VERSION 5.8 ;
BUSBITCHARS "[]" ;
DIVIDERCHAR "/" ;
UNITS
    DATABASE MICRONS 1000 ;
END UNITS

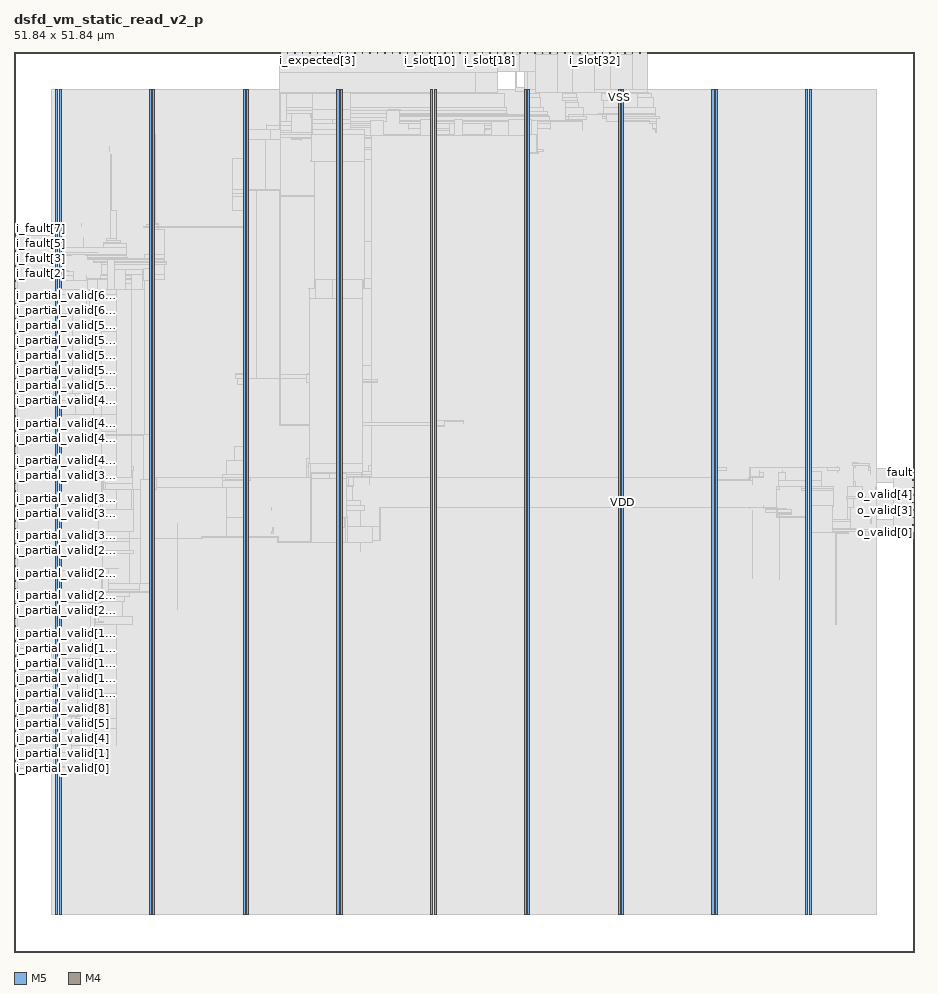
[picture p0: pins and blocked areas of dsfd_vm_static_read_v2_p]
MACRO dsfd_vm_static_read_v2_p
  FOREIGN dsfd_vm_static_read_v2_p 0 0 ;
  CLASS BLOCK ;
  SIZE 51.84 BY 51.84 ;
  PIN ck
    DIRECTION INPUT ;
    USE SIGNAL ;
    PORT
      LAYER M5 ;
        RECT  15.312 51.756 15.336 51.84 ;
    END
  END ck
  PIN fault
    DIRECTION OUTPUT ;
    USE SIGNAL ;
    PORT
      LAYER M4 ;
        RECT  51.756 27.6 51.84 27.624 ;
    END
  END fault
  PIN i_expected[0]
    DIRECTION INPUT ;
    USE SIGNAL ;
    PORT
      LAYER M5 ;
        RECT  16.176 51.756 16.2 51.84 ;
    END
  END i_expected[0]
  PIN i_expected[1]
    DIRECTION INPUT ;
    USE SIGNAL ;
    PORT
      LAYER M5 ;
        RECT  16.608 51.756 16.632 51.84 ;
    END
  END i_expected[1]
  PIN i_expected[2]
    DIRECTION INPUT ;
    USE SIGNAL ;
    PORT
      LAYER M5 ;
        RECT  17.04 51.756 17.064 51.84 ;
    END
  END i_expected[2]
  PIN i_expected[3]
    DIRECTION INPUT ;
    USE SIGNAL ;
    PORT
      LAYER M5 ;
        RECT  17.472 51.756 17.496 51.84 ;
    END
  END i_expected[3]
  PIN i_expected[4]
    DIRECTION INPUT ;
    USE SIGNAL ;
    PORT
      LAYER M5 ;
        RECT  17.904 51.756 17.928 51.84 ;
    END
  END i_expected[4]
  PIN i_expected[5]
    DIRECTION INPUT ;
    USE SIGNAL ;
    PORT
      LAYER M5 ;
        RECT  18.336 51.756 18.36 51.84 ;
    END
  END i_expected[5]
  PIN i_expected[6]
    DIRECTION INPUT ;
    USE SIGNAL ;
    PORT
      LAYER M5 ;
        RECT  18.768 51.756 18.792 51.84 ;
    END
  END i_expected[6]
  PIN i_expected[7]
    DIRECTION INPUT ;
    USE SIGNAL ;
    PORT
      LAYER M5 ;
        RECT  19.2 51.756 19.224 51.84 ;
    END
  END i_expected[7]
  PIN i_fault[0]
    DIRECTION INPUT ;
    USE SIGNAL ;
    PORT
      LAYER M4 ;
        RECT  0 38.208 0.084 38.232 ;
    END
  END i_fault[0]
  PIN i_fault[1]
    DIRECTION INPUT ;
    USE SIGNAL ;
    PORT
      LAYER M4 ;
        RECT  0 38.64 0.084 38.664 ;
    END
  END i_fault[1]
  PIN i_fault[2]
    DIRECTION INPUT ;
    USE SIGNAL ;
    PORT
      LAYER M4 ;
        RECT  0 39.072 0.084 39.096 ;
    END
  END i_fault[2]
  PIN i_fault[3]
    DIRECTION INPUT ;
    USE SIGNAL ;
    PORT
      LAYER M4 ;
        RECT  0 39.504 0.084 39.528 ;
    END
  END i_fault[3]
  PIN i_fault[4]
    DIRECTION INPUT ;
    USE SIGNAL ;
    PORT
      LAYER M4 ;
        RECT  0 39.936 0.084 39.96 ;
    END
  END i_fault[4]
  PIN i_fault[5]
    DIRECTION INPUT ;
    USE SIGNAL ;
    PORT
      LAYER M4 ;
        RECT  0 40.368 0.084 40.392 ;
    END
  END i_fault[5]
  PIN i_fault[6]
    DIRECTION INPUT ;
    USE SIGNAL ;
    PORT
      LAYER M4 ;
        RECT  0 40.8 0.084 40.824 ;
    END
  END i_fault[6]
  PIN i_fault[7]
    DIRECTION INPUT ;
    USE SIGNAL ;
    PORT
      LAYER M4 ;
        RECT  0 41.232 0.084 41.256 ;
    END
  END i_fault[7]
  PIN i_partial_valid[0]
    DIRECTION INPUT ;
    USE SIGNAL ;
    PORT
      LAYER M4 ;
        RECT  0 10.56 0.084 10.584 ;
    END
  END i_partial_valid[0]
  PIN i_partial_valid[10]
    DIRECTION INPUT ;
    USE SIGNAL ;
    PORT
      LAYER M4 ;
        RECT  0 14.88 0.084 14.904 ;
    END
  END i_partial_valid[10]
  PIN i_partial_valid[11]
    DIRECTION INPUT ;
    USE SIGNAL ;
    PORT
      LAYER M4 ;
        RECT  0 15.312 0.084 15.336 ;
    END
  END i_partial_valid[11]
  PIN i_partial_valid[12]
    DIRECTION INPUT ;
    USE SIGNAL ;
    PORT
      LAYER M4 ;
        RECT  0 15.744 0.084 15.768 ;
    END
  END i_partial_valid[12]
  PIN i_partial_valid[13]
    DIRECTION INPUT ;
    USE SIGNAL ;
    PORT
      LAYER M4 ;
        RECT  0 16.176 0.084 16.2 ;
    END
  END i_partial_valid[13]
  PIN i_partial_valid[14]
    DIRECTION INPUT ;
    USE SIGNAL ;
    PORT
      LAYER M4 ;
        RECT  0 16.608 0.084 16.632 ;
    END
  END i_partial_valid[14]
  PIN i_partial_valid[15]
    DIRECTION INPUT ;
    USE SIGNAL ;
    PORT
      LAYER M4 ;
        RECT  0 17.04 0.084 17.064 ;
    END
  END i_partial_valid[15]
  PIN i_partial_valid[16]
    DIRECTION INPUT ;
    USE SIGNAL ;
    PORT
      LAYER M4 ;
        RECT  0 17.472 0.084 17.496 ;
    END
  END i_partial_valid[16]
  PIN i_partial_valid[17]
    DIRECTION INPUT ;
    USE SIGNAL ;
    PORT
      LAYER M4 ;
        RECT  0 17.904 0.084 17.928 ;
    END
  END i_partial_valid[17]
  PIN i_partial_valid[18]
    DIRECTION INPUT ;
    USE SIGNAL ;
    PORT
      LAYER M4 ;
        RECT  0 18.336 0.084 18.36 ;
    END
  END i_partial_valid[18]
  PIN i_partial_valid[19]
    DIRECTION INPUT ;
    USE SIGNAL ;
    PORT
      LAYER M4 ;
        RECT  0 18.768 0.084 18.792 ;
    END
  END i_partial_valid[19]
  PIN i_partial_valid[1]
    DIRECTION INPUT ;
    USE SIGNAL ;
    PORT
      LAYER M4 ;
        RECT  0 10.992 0.084 11.016 ;
    END
  END i_partial_valid[1]
  PIN i_partial_valid[20]
    DIRECTION INPUT ;
    USE SIGNAL ;
    PORT
      LAYER M4 ;
        RECT  0 19.2 0.084 19.224 ;
    END
  END i_partial_valid[20]
  PIN i_partial_valid[21]
    DIRECTION INPUT ;
    USE SIGNAL ;
    PORT
      LAYER M4 ;
        RECT  0 19.632 0.084 19.656 ;
    END
  END i_partial_valid[21]
  PIN i_partial_valid[22]
    DIRECTION INPUT ;
    USE SIGNAL ;
    PORT
      LAYER M4 ;
        RECT  0 20.064 0.084 20.088 ;
    END
  END i_partial_valid[22]
  PIN i_partial_valid[23]
    DIRECTION INPUT ;
    USE SIGNAL ;
    PORT
      LAYER M4 ;
        RECT  0 20.496 0.084 20.52 ;
    END
  END i_partial_valid[23]
  PIN i_partial_valid[24]
    DIRECTION INPUT ;
    USE SIGNAL ;
    PORT
      LAYER M4 ;
        RECT  0 20.928 0.084 20.952 ;
    END
  END i_partial_valid[24]
  PIN i_partial_valid[25]
    DIRECTION INPUT ;
    USE SIGNAL ;
    PORT
      LAYER M4 ;
        RECT  0 21.36 0.084 21.384 ;
    END
  END i_partial_valid[25]
  PIN i_partial_valid[26]
    DIRECTION INPUT ;
    USE SIGNAL ;
    PORT
      LAYER M4 ;
        RECT  0 21.792 0.084 21.816 ;
    END
  END i_partial_valid[26]
  PIN i_partial_valid[27]
    DIRECTION INPUT ;
    USE SIGNAL ;
    PORT
      LAYER M4 ;
        RECT  0 22.224 0.084 22.248 ;
    END
  END i_partial_valid[27]
  PIN i_partial_valid[28]
    DIRECTION INPUT ;
    USE SIGNAL ;
    PORT
      LAYER M4 ;
        RECT  0 22.656 0.084 22.68 ;
    END
  END i_partial_valid[28]
  PIN i_partial_valid[29]
    DIRECTION INPUT ;
    USE SIGNAL ;
    PORT
      LAYER M4 ;
        RECT  0 23.088 0.084 23.112 ;
    END
  END i_partial_valid[29]
  PIN i_partial_valid[2]
    DIRECTION INPUT ;
    USE SIGNAL ;
    PORT
      LAYER M4 ;
        RECT  0 11.424 0.084 11.448 ;
    END
  END i_partial_valid[2]
  PIN i_partial_valid[30]
    DIRECTION INPUT ;
    USE SIGNAL ;
    PORT
      LAYER M4 ;
        RECT  0 23.52 0.084 23.544 ;
    END
  END i_partial_valid[30]
  PIN i_partial_valid[31]
    DIRECTION INPUT ;
    USE SIGNAL ;
    PORT
      LAYER M4 ;
        RECT  0 23.952 0.084 23.976 ;
    END
  END i_partial_valid[31]
  PIN i_partial_valid[32]
    DIRECTION INPUT ;
    USE SIGNAL ;
    PORT
      LAYER M4 ;
        RECT  0 24.384 0.084 24.408 ;
    END
  END i_partial_valid[32]
  PIN i_partial_valid[33]
    DIRECTION INPUT ;
    USE SIGNAL ;
    PORT
      LAYER M4 ;
        RECT  0 24.816 0.084 24.84 ;
    END
  END i_partial_valid[33]
  PIN i_partial_valid[34]
    DIRECTION INPUT ;
    USE SIGNAL ;
    PORT
      LAYER M4 ;
        RECT  0 25.248 0.084 25.272 ;
    END
  END i_partial_valid[34]
  PIN i_partial_valid[35]
    DIRECTION INPUT ;
    USE SIGNAL ;
    PORT
      LAYER M4 ;
        RECT  0 25.68 0.084 25.704 ;
    END
  END i_partial_valid[35]
  PIN i_partial_valid[36]
    DIRECTION INPUT ;
    USE SIGNAL ;
    PORT
      LAYER M4 ;
        RECT  0 26.112 0.084 26.136 ;
    END
  END i_partial_valid[36]
  PIN i_partial_valid[37]
    DIRECTION INPUT ;
    USE SIGNAL ;
    PORT
      LAYER M4 ;
        RECT  0 26.544 0.084 26.568 ;
    END
  END i_partial_valid[37]
  PIN i_partial_valid[38]
    DIRECTION INPUT ;
    USE SIGNAL ;
    PORT
      LAYER M4 ;
        RECT  0 26.976 0.084 27 ;
    END
  END i_partial_valid[38]
  PIN i_partial_valid[39]
    DIRECTION INPUT ;
    USE SIGNAL ;
    PORT
      LAYER M4 ;
        RECT  0 27.408 0.084 27.432 ;
    END
  END i_partial_valid[39]
  PIN i_partial_valid[3]
    DIRECTION INPUT ;
    USE SIGNAL ;
    PORT
      LAYER M4 ;
        RECT  0 11.856 0.084 11.88 ;
    END
  END i_partial_valid[3]
  PIN i_partial_valid[40]
    DIRECTION INPUT ;
    USE SIGNAL ;
    PORT
      LAYER M4 ;
        RECT  0 27.84 0.084 27.864 ;
    END
  END i_partial_valid[40]
  PIN i_partial_valid[41]
    DIRECTION INPUT ;
    USE SIGNAL ;
    PORT
      LAYER M4 ;
        RECT  0 28.272 0.084 28.296 ;
    END
  END i_partial_valid[41]
  PIN i_partial_valid[42]
    DIRECTION INPUT ;
    USE SIGNAL ;
    PORT
      LAYER M4 ;
        RECT  0 28.704 0.084 28.728 ;
    END
  END i_partial_valid[42]
  PIN i_partial_valid[43]
    DIRECTION INPUT ;
    USE SIGNAL ;
    PORT
      LAYER M4 ;
        RECT  0 29.136 0.084 29.16 ;
    END
  END i_partial_valid[43]
  PIN i_partial_valid[44]
    DIRECTION INPUT ;
    USE SIGNAL ;
    PORT
      LAYER M4 ;
        RECT  0 29.568 0.084 29.592 ;
    END
  END i_partial_valid[44]
  PIN i_partial_valid[45]
    DIRECTION INPUT ;
    USE SIGNAL ;
    PORT
      LAYER M4 ;
        RECT  0 30 0.084 30.024 ;
    END
  END i_partial_valid[45]
  PIN i_partial_valid[46]
    DIRECTION INPUT ;
    USE SIGNAL ;
    PORT
      LAYER M4 ;
        RECT  0 30.432 0.084 30.456 ;
    END
  END i_partial_valid[46]
  PIN i_partial_valid[47]
    DIRECTION INPUT ;
    USE SIGNAL ;
    PORT
      LAYER M4 ;
        RECT  0 30.864 0.084 30.888 ;
    END
  END i_partial_valid[47]
  PIN i_partial_valid[48]
    DIRECTION INPUT ;
    USE SIGNAL ;
    PORT
      LAYER M4 ;
        RECT  0 31.296 0.084 31.32 ;
    END
  END i_partial_valid[48]
  PIN i_partial_valid[49]
    DIRECTION INPUT ;
    USE SIGNAL ;
    PORT
      LAYER M4 ;
        RECT  0 31.728 0.084 31.752 ;
    END
  END i_partial_valid[49]
  PIN i_partial_valid[4]
    DIRECTION INPUT ;
    USE SIGNAL ;
    PORT
      LAYER M4 ;
        RECT  0 12.288 0.084 12.312 ;
    END
  END i_partial_valid[4]
  PIN i_partial_valid[50]
    DIRECTION INPUT ;
    USE SIGNAL ;
    PORT
      LAYER M4 ;
        RECT  0 32.16 0.084 32.184 ;
    END
  END i_partial_valid[50]
  PIN i_partial_valid[51]
    DIRECTION INPUT ;
    USE SIGNAL ;
    PORT
      LAYER M4 ;
        RECT  0 32.592 0.084 32.616 ;
    END
  END i_partial_valid[51]
  PIN i_partial_valid[52]
    DIRECTION INPUT ;
    USE SIGNAL ;
    PORT
      LAYER M4 ;
        RECT  0 33.024 0.084 33.048 ;
    END
  END i_partial_valid[52]
  PIN i_partial_valid[53]
    DIRECTION INPUT ;
    USE SIGNAL ;
    PORT
      LAYER M4 ;
        RECT  0 33.456 0.084 33.48 ;
    END
  END i_partial_valid[53]
  PIN i_partial_valid[54]
    DIRECTION INPUT ;
    USE SIGNAL ;
    PORT
      LAYER M4 ;
        RECT  0 33.888 0.084 33.912 ;
    END
  END i_partial_valid[54]
  PIN i_partial_valid[55]
    DIRECTION INPUT ;
    USE SIGNAL ;
    PORT
      LAYER M4 ;
        RECT  0 34.32 0.084 34.344 ;
    END
  END i_partial_valid[55]
  PIN i_partial_valid[56]
    DIRECTION INPUT ;
    USE SIGNAL ;
    PORT
      LAYER M4 ;
        RECT  0 34.752 0.084 34.776 ;
    END
  END i_partial_valid[56]
  PIN i_partial_valid[57]
    DIRECTION INPUT ;
    USE SIGNAL ;
    PORT
      LAYER M4 ;
        RECT  0 35.184 0.084 35.208 ;
    END
  END i_partial_valid[57]
  PIN i_partial_valid[58]
    DIRECTION INPUT ;
    USE SIGNAL ;
    PORT
      LAYER M4 ;
        RECT  0 35.616 0.084 35.64 ;
    END
  END i_partial_valid[58]
  PIN i_partial_valid[59]
    DIRECTION INPUT ;
    USE SIGNAL ;
    PORT
      LAYER M4 ;
        RECT  0 36.048 0.084 36.072 ;
    END
  END i_partial_valid[59]
  PIN i_partial_valid[5]
    DIRECTION INPUT ;
    USE SIGNAL ;
    PORT
      LAYER M4 ;
        RECT  0 12.72 0.084 12.744 ;
    END
  END i_partial_valid[5]
  PIN i_partial_valid[60]
    DIRECTION INPUT ;
    USE SIGNAL ;
    PORT
      LAYER M4 ;
        RECT  0 36.48 0.084 36.504 ;
    END
  END i_partial_valid[60]
  PIN i_partial_valid[61]
    DIRECTION INPUT ;
    USE SIGNAL ;
    PORT
      LAYER M4 ;
        RECT  0 36.912 0.084 36.936 ;
    END
  END i_partial_valid[61]
  PIN i_partial_valid[62]
    DIRECTION INPUT ;
    USE SIGNAL ;
    PORT
      LAYER M4 ;
        RECT  0 37.344 0.084 37.368 ;
    END
  END i_partial_valid[62]
  PIN i_partial_valid[63]
    DIRECTION INPUT ;
    USE SIGNAL ;
    PORT
      LAYER M4 ;
        RECT  0 37.776 0.084 37.8 ;
    END
  END i_partial_valid[63]
  PIN i_partial_valid[6]
    DIRECTION INPUT ;
    USE SIGNAL ;
    PORT
      LAYER M4 ;
        RECT  0 13.152 0.084 13.176 ;
    END
  END i_partial_valid[6]
  PIN i_partial_valid[7]
    DIRECTION INPUT ;
    USE SIGNAL ;
    PORT
      LAYER M4 ;
        RECT  0 13.584 0.084 13.608 ;
    END
  END i_partial_valid[7]
  PIN i_partial_valid[8]
    DIRECTION INPUT ;
    USE SIGNAL ;
    PORT
      LAYER M4 ;
        RECT  0 14.016 0.084 14.04 ;
    END
  END i_partial_valid[8]
  PIN i_partial_valid[9]
    DIRECTION INPUT ;
    USE SIGNAL ;
    PORT
      LAYER M4 ;
        RECT  0 14.448 0.084 14.472 ;
    END
  END i_partial_valid[9]
  PIN i_slot[0]
    DIRECTION INPUT ;
    USE SIGNAL ;
    PORT
      LAYER M5 ;
        RECT  19.632 51.756 19.656 51.84 ;
    END
  END i_slot[0]
  PIN i_slot[10]
    DIRECTION INPUT ;
    USE SIGNAL ;
    PORT
      LAYER M5 ;
        RECT  23.952 51.756 23.976 51.84 ;
    END
  END i_slot[10]
  PIN i_slot[11]
    DIRECTION INPUT ;
    USE SIGNAL ;
    PORT
      LAYER M5 ;
        RECT  24.384 51.756 24.408 51.84 ;
    END
  END i_slot[11]
  PIN i_slot[12]
    DIRECTION INPUT ;
    USE SIGNAL ;
    PORT
      LAYER M5 ;
        RECT  24.816 51.756 24.84 51.84 ;
    END
  END i_slot[12]
  PIN i_slot[13]
    DIRECTION INPUT ;
    USE SIGNAL ;
    PORT
      LAYER M5 ;
        RECT  25.248 51.756 25.272 51.84 ;
    END
  END i_slot[13]
  PIN i_slot[14]
    DIRECTION INPUT ;
    USE SIGNAL ;
    PORT
      LAYER M5 ;
        RECT  25.68 51.756 25.704 51.84 ;
    END
  END i_slot[14]
  PIN i_slot[15]
    DIRECTION INPUT ;
    USE SIGNAL ;
    PORT
      LAYER M5 ;
        RECT  26.112 51.756 26.136 51.84 ;
    END
  END i_slot[15]
  PIN i_slot[16]
    DIRECTION INPUT ;
    USE SIGNAL ;
    PORT
      LAYER M5 ;
        RECT  26.544 51.756 26.568 51.84 ;
    END
  END i_slot[16]
  PIN i_slot[17]
    DIRECTION INPUT ;
    USE SIGNAL ;
    PORT
      LAYER M5 ;
        RECT  26.976 51.756 27 51.84 ;
    END
  END i_slot[17]
  PIN i_slot[18]
    DIRECTION INPUT ;
    USE SIGNAL ;
    PORT
      LAYER M5 ;
        RECT  27.408 51.756 27.432 51.84 ;
    END
  END i_slot[18]
  PIN i_slot[19]
    DIRECTION INPUT ;
    USE SIGNAL ;
    PORT
      LAYER M5 ;
        RECT  27.84 51.756 27.864 51.84 ;
    END
  END i_slot[19]
  PIN i_slot[1]
    DIRECTION INPUT ;
    USE SIGNAL ;
    PORT
      LAYER M5 ;
        RECT  20.064 51.756 20.088 51.84 ;
    END
  END i_slot[1]
  PIN i_slot[20]
    DIRECTION INPUT ;
    USE SIGNAL ;
    PORT
      LAYER M5 ;
        RECT  28.272 51.756 28.296 51.84 ;
    END
  END i_slot[20]
  PIN i_slot[21]
    DIRECTION INPUT ;
    USE SIGNAL ;
    PORT
      LAYER M5 ;
        RECT  28.704 51.756 28.728 51.84 ;
    END
  END i_slot[21]
  PIN i_slot[22]
    DIRECTION INPUT ;
    USE SIGNAL ;
    PORT
      LAYER M5 ;
        RECT  29.136 51.756 29.16 51.84 ;
    END
  END i_slot[22]
  PIN i_slot[23]
    DIRECTION INPUT ;
    USE SIGNAL ;
    PORT
      LAYER M5 ;
        RECT  29.568 51.756 29.592 51.84 ;
    END
  END i_slot[23]
  PIN i_slot[24]
    DIRECTION INPUT ;
    USE SIGNAL ;
    PORT
      LAYER M5 ;
        RECT  30 51.756 30.024 51.84 ;
    END
  END i_slot[24]
  PIN i_slot[25]
    DIRECTION INPUT ;
    USE SIGNAL ;
    PORT
      LAYER M5 ;
        RECT  30.432 51.756 30.456 51.84 ;
    END
  END i_slot[25]
  PIN i_slot[26]
    DIRECTION INPUT ;
    USE SIGNAL ;
    PORT
      LAYER M5 ;
        RECT  30.864 51.756 30.888 51.84 ;
    END
  END i_slot[26]
  PIN i_slot[27]
    DIRECTION INPUT ;
    USE SIGNAL ;
    PORT
      LAYER M5 ;
        RECT  31.296 51.756 31.32 51.84 ;
    END
  END i_slot[27]
  PIN i_slot[28]
    DIRECTION INPUT ;
    USE SIGNAL ;
    PORT
      LAYER M5 ;
        RECT  31.728 51.756 31.752 51.84 ;
    END
  END i_slot[28]
  PIN i_slot[29]
    DIRECTION INPUT ;
    USE SIGNAL ;
    PORT
      LAYER M5 ;
        RECT  32.16 51.756 32.184 51.84 ;
    END
  END i_slot[29]
  PIN i_slot[2]
    DIRECTION INPUT ;
    USE SIGNAL ;
    PORT
      LAYER M5 ;
        RECT  20.496 51.756 20.52 51.84 ;
    END
  END i_slot[2]
  PIN i_slot[30]
    DIRECTION INPUT ;
    USE SIGNAL ;
    PORT
      LAYER M5 ;
        RECT  32.592 51.756 32.616 51.84 ;
    END
  END i_slot[30]
  PIN i_slot[31]
    DIRECTION INPUT ;
    USE SIGNAL ;
    PORT
      LAYER M5 ;
        RECT  33.024 51.756 33.048 51.84 ;
    END
  END i_slot[31]
  PIN i_slot[32]
    DIRECTION INPUT ;
    USE SIGNAL ;
    PORT
      LAYER M5 ;
        RECT  33.456 51.756 33.48 51.84 ;
    END
  END i_slot[32]
  PIN i_slot[33]
    DIRECTION INPUT ;
    USE SIGNAL ;
    PORT
      LAYER M5 ;
        RECT  33.888 51.756 33.912 51.84 ;
    END
  END i_slot[33]
  PIN i_slot[34]
    DIRECTION INPUT ;
    USE SIGNAL ;
    PORT
      LAYER M5 ;
        RECT  34.32 51.756 34.344 51.84 ;
    END
  END i_slot[34]
  PIN i_slot[35]
    DIRECTION INPUT ;
    USE SIGNAL ;
    PORT
      LAYER M5 ;
        RECT  34.752 51.756 34.776 51.84 ;
    END
  END i_slot[35]
  PIN i_slot[36]
    DIRECTION INPUT ;
    USE SIGNAL ;
    PORT
      LAYER M5 ;
        RECT  35.184 51.756 35.208 51.84 ;
    END
  END i_slot[36]
  PIN i_slot[37]
    DIRECTION INPUT ;
    USE SIGNAL ;
    PORT
      LAYER M5 ;
        RECT  35.616 51.756 35.64 51.84 ;
    END
  END i_slot[37]
  PIN i_slot[38]
    DIRECTION INPUT ;
    USE SIGNAL ;
    PORT
      LAYER M5 ;
        RECT  36.048 51.756 36.072 51.84 ;
    END
  END i_slot[38]
  PIN i_slot[39]
    DIRECTION INPUT ;
    USE SIGNAL ;
    PORT
      LAYER M5 ;
        RECT  36.48 51.756 36.504 51.84 ;
    END
  END i_slot[39]
  PIN i_slot[3]
    DIRECTION INPUT ;
    USE SIGNAL ;
    PORT
      LAYER M5 ;
        RECT  20.928 51.756 20.952 51.84 ;
    END
  END i_slot[3]
  PIN i_slot[4]
    DIRECTION INPUT ;
    USE SIGNAL ;
    PORT
      LAYER M5 ;
        RECT  21.36 51.756 21.384 51.84 ;
    END
  END i_slot[4]
  PIN i_slot[5]
    DIRECTION INPUT ;
    USE SIGNAL ;
    PORT
      LAYER M5 ;
        RECT  21.792 51.756 21.816 51.84 ;
    END
  END i_slot[5]
  PIN i_slot[6]
    DIRECTION INPUT ;
    USE SIGNAL ;
    PORT
      LAYER M5 ;
        RECT  22.224 51.756 22.248 51.84 ;
    END
  END i_slot[6]
  PIN i_slot[7]
    DIRECTION INPUT ;
    USE SIGNAL ;
    PORT
      LAYER M5 ;
        RECT  22.656 51.756 22.68 51.84 ;
    END
  END i_slot[7]
  PIN i_slot[8]
    DIRECTION INPUT ;
    USE SIGNAL ;
    PORT
      LAYER M5 ;
        RECT  23.088 51.756 23.112 51.84 ;
    END
  END i_slot[8]
  PIN i_slot[9]
    DIRECTION INPUT ;
    USE SIGNAL ;
    PORT
      LAYER M5 ;
        RECT  23.52 51.756 23.544 51.84 ;
    END
  END i_slot[9]
  PIN o_valid[0]
    DIRECTION OUTPUT ;
    USE SIGNAL ;
    PORT
      LAYER M4 ;
        RECT  51.756 24.144 51.84 24.168 ;
    END
  END o_valid[0]
  PIN o_valid[1]
    DIRECTION OUTPUT ;
    USE SIGNAL ;
    PORT
      LAYER M4 ;
        RECT  51.756 24.576 51.84 24.6 ;
    END
  END o_valid[1]
  PIN o_valid[2]
    DIRECTION OUTPUT ;
    USE SIGNAL ;
    PORT
      LAYER M4 ;
        RECT  51.756 25.008 51.84 25.032 ;
    END
  END o_valid[2]
  PIN o_valid[3]
    DIRECTION OUTPUT ;
    USE SIGNAL ;
    PORT
      LAYER M4 ;
        RECT  51.756 25.44 51.84 25.464 ;
    END
  END o_valid[3]
  PIN o_valid[4]
    DIRECTION OUTPUT ;
    USE SIGNAL ;
    PORT
      LAYER M4 ;
        RECT  51.756 25.872 51.84 25.896 ;
    END
  END o_valid[4]
  PIN o_valid[5]
    DIRECTION OUTPUT ;
    USE SIGNAL ;
    PORT
      LAYER M4 ;
        RECT  51.756 26.304 51.84 26.328 ;
    END
  END o_valid[5]
  PIN o_valid[6]
    DIRECTION OUTPUT ;
    USE SIGNAL ;
    PORT
      LAYER M4 ;
        RECT  51.756 26.736 51.84 26.76 ;
    END
  END o_valid[6]
  PIN o_valid[7]
    DIRECTION OUTPUT ;
    USE SIGNAL ;
    PORT
      LAYER M4 ;
        RECT  51.756 27.168 51.84 27.192 ;
    END
  END o_valid[7]
  PIN rst_n
    DIRECTION INPUT ;
    USE SIGNAL ;
    PORT
      LAYER M5 ;
        RECT  15.744 51.756 15.768 51.84 ;
    END
  END rst_n
  PIN VDD
    DIRECTION INOUT ;
    USE POWER ;
    PORT
      LAYER M5 ;
        RECT  45.792 2.151 45.912 49.689 ;
        RECT  40.392 2.151 40.512 49.689 ;
        RECT  34.992 2.151 35.112 49.689 ;
        RECT  29.592 2.151 29.712 49.689 ;
        RECT  24.192 2.151 24.312 49.689 ;
        RECT  18.792 2.151 18.912 49.689 ;
        RECT  13.392 2.151 13.512 49.689 ;
        RECT  7.992 2.151 8.112 49.689 ;
        RECT  2.592 2.151 2.712 49.689 ;
    END
  END VDD
  PIN VSS
    DIRECTION INOUT ;
    USE GROUND ;
    PORT
      LAYER M5 ;
        RECT  45.6 2.137 45.72 49.703 ;
        RECT  40.2 2.137 40.32 49.703 ;
        RECT  34.8 2.137 34.92 49.703 ;
        RECT  29.4 2.137 29.52 49.703 ;
        RECT  24 2.137 24.12 49.703 ;
        RECT  18.6 2.137 18.72 49.703 ;
        RECT  13.2 2.137 13.32 49.703 ;
        RECT  7.8 2.137 7.92 49.703 ;
        RECT  2.4 2.137 2.52 49.703 ;
    END
  END VSS
  # OT_OBS_CLOSED layer=M5 d_um=1.536 added=34
  OBS
    LAYER RVTN ;
     RECT  2.16 2.16 49.68 2.295 ;
     RECT  2.16 2.565 49.68 2.835 ;
     RECT  2.16 3.105 49.68 3.375 ;
     RECT  2.16 3.645 49.68 3.915 ;
     RECT  2.16 4.185 49.68 4.455 ;
     RECT  2.16 4.725 49.68 4.995 ;
     RECT  2.16 5.265 49.68 5.535 ;
     RECT  2.16 5.805 49.68 6.075 ;
     RECT  2.16 6.345 49.68 6.615 ;
     RECT  2.16 6.885 49.68 7.155 ;
     RECT  2.16 7.425 49.68 7.695 ;
     RECT  2.16 7.965 49.68 8.235 ;
     RECT  2.16 8.505 49.68 8.775 ;
     RECT  2.16 9.045 49.68 9.315 ;
     RECT  2.16 9.585 49.68 9.855 ;
     RECT  2.16 10.125 49.68 10.395 ;
     RECT  2.16 10.665 49.68 10.935 ;
     RECT  2.16 11.205 49.68 11.475 ;
     RECT  2.16 11.745 49.68 12.015 ;
     RECT  2.16 12.285 49.68 12.555 ;
     RECT  2.16 12.825 49.68 13.095 ;
     RECT  2.16 13.365 49.68 13.635 ;
     RECT  2.16 13.905 49.68 14.175 ;
     RECT  2.16 14.445 49.68 14.715 ;
     RECT  2.16 14.985 49.68 15.255 ;
     RECT  2.16 15.525 49.68 15.795 ;
     RECT  2.16 16.065 49.68 16.335 ;
     RECT  2.16 16.605 49.68 16.875 ;
     RECT  2.16 17.145 49.68 17.415 ;
     RECT  2.16 17.685 49.68 17.955 ;
     RECT  2.16 18.225 49.68 18.495 ;
     RECT  2.16 18.765 49.68 19.035 ;
     RECT  2.16 19.305 49.68 19.575 ;
     RECT  2.16 19.845 49.68 20.115 ;
     RECT  2.16 20.385 49.68 20.655 ;
     RECT  2.16 20.925 49.68 21.195 ;
     RECT  2.16 21.465 49.68 21.735 ;
     RECT  2.16 22.005 49.68 22.275 ;
     RECT  2.16 22.545 49.68 22.815 ;
     RECT  2.16 23.085 49.68 23.355 ;
     RECT  2.16 23.625 49.68 23.895 ;
     RECT  2.16 24.165 49.68 24.435 ;
     RECT  2.16 24.705 49.68 24.975 ;
     RECT  2.16 25.245 49.68 25.515 ;
     RECT  2.16 25.785 49.68 26.055 ;
     RECT  2.16 26.325 49.68 26.595 ;
     RECT  2.16 26.865 49.68 27.135 ;
     RECT  2.16 27.405 49.68 27.675 ;
     RECT  2.16 27.945 49.68 28.215 ;
     RECT  2.16 28.485 49.68 28.755 ;
     RECT  2.16 29.025 49.68 29.295 ;
     RECT  2.16 29.565 49.68 29.835 ;
     RECT  2.16 30.105 49.68 30.375 ;
     RECT  2.16 30.645 49.68 30.915 ;
     RECT  2.16 31.185 49.68 31.455 ;
     RECT  2.16 31.725 49.68 31.995 ;
     RECT  2.16 32.265 49.68 32.535 ;
     RECT  2.16 32.805 49.68 33.075 ;
     RECT  2.16 33.345 49.68 33.615 ;
     RECT  2.16 33.885 49.68 34.155 ;
     RECT  2.16 34.425 49.68 34.695 ;
     RECT  2.16 34.965 49.68 35.235 ;
     RECT  2.16 35.505 49.68 35.775 ;
     RECT  2.16 36.045 49.68 36.315 ;
     RECT  2.16 36.585 49.68 36.855 ;
     RECT  2.16 37.125 49.68 37.395 ;
     RECT  2.16 37.665 49.68 37.935 ;
     RECT  2.16 38.205 49.68 38.475 ;
     RECT  2.16 38.745 49.68 39.015 ;
     RECT  2.16 39.285 49.68 39.555 ;
     RECT  2.16 39.825 49.68 40.095 ;
     RECT  2.16 40.365 49.68 40.635 ;
     RECT  2.16 40.905 49.68 41.175 ;
     RECT  2.16 41.445 49.68 41.715 ;
     RECT  2.16 41.985 49.68 42.255 ;
     RECT  2.16 42.525 49.68 42.795 ;
     RECT  2.16 43.065 49.68 43.335 ;
     RECT  2.16 43.605 49.68 43.875 ;
     RECT  2.16 44.145 49.68 44.415 ;
     RECT  2.16 44.685 49.68 44.955 ;
     RECT  2.16 45.225 49.68 45.495 ;
     RECT  2.16 45.765 49.68 46.035 ;
     RECT  2.16 46.305 49.68 46.575 ;
     RECT  2.16 46.845 49.68 47.115 ;
     RECT  2.16 47.385 49.68 47.655 ;
     RECT  2.16 47.925 49.68 48.195 ;
     RECT  2.16 48.465 49.68 48.735 ;
     RECT  2.16 49.005 49.68 49.275 ;
     RECT  2.16 49.545 49.68 49.68 ;
    LAYER RVTP ;
     RECT  2.16 2.295 49.68 2.565 ;
     RECT  2.16 2.835 49.68 3.105 ;
     RECT  2.16 3.375 49.68 3.645 ;
     RECT  2.16 3.915 49.68 4.185 ;
     RECT  2.16 4.455 49.68 4.725 ;
     RECT  2.16 4.995 49.68 5.265 ;
     RECT  2.16 5.535 49.68 5.805 ;
     RECT  2.16 6.075 49.68 6.345 ;
     RECT  2.16 6.615 49.68 6.885 ;
     RECT  2.16 7.155 49.68 7.425 ;
     RECT  2.16 7.695 49.68 7.965 ;
     RECT  2.16 8.235 49.68 8.505 ;
     RECT  2.16 8.775 49.68 9.045 ;
     RECT  2.16 9.315 49.68 9.585 ;
     RECT  2.16 9.855 49.68 10.125 ;
     RECT  2.16 10.395 49.68 10.665 ;
     RECT  2.16 10.935 49.68 11.205 ;
     RECT  2.16 11.475 49.68 11.745 ;
     RECT  2.16 12.015 49.68 12.285 ;
     RECT  2.16 12.555 49.68 12.825 ;
     RECT  2.16 13.095 49.68 13.365 ;
     RECT  2.16 13.635 49.68 13.905 ;
     RECT  2.16 14.175 49.68 14.445 ;
     RECT  2.16 14.715 49.68 14.985 ;
     RECT  2.16 15.255 49.68 15.525 ;
     RECT  2.16 15.795 49.68 16.065 ;
     RECT  2.16 16.335 49.68 16.605 ;
     RECT  2.16 16.875 49.68 17.145 ;
     RECT  2.16 17.415 49.68 17.685 ;
     RECT  2.16 17.955 49.68 18.225 ;
     RECT  2.16 18.495 49.68 18.765 ;
     RECT  2.16 19.035 49.68 19.305 ;
     RECT  2.16 19.575 49.68 19.845 ;
     RECT  2.16 20.115 49.68 20.385 ;
     RECT  2.16 20.655 49.68 20.925 ;
     RECT  2.16 21.195 49.68 21.465 ;
     RECT  2.16 21.735 49.68 22.005 ;
     RECT  2.16 22.275 49.68 22.545 ;
     RECT  2.16 22.815 49.68 23.085 ;
     RECT  2.16 23.355 49.68 23.625 ;
     RECT  2.16 23.895 49.68 24.165 ;
     RECT  2.16 24.435 49.68 24.705 ;
     RECT  2.16 24.975 49.68 25.245 ;
     RECT  2.16 25.515 49.68 25.785 ;
     RECT  2.16 26.055 49.68 26.325 ;
     RECT  2.16 26.595 49.68 26.865 ;
     RECT  2.16 27.135 49.68 27.405 ;
     RECT  2.16 27.675 49.68 27.945 ;
     RECT  2.16 28.215 49.68 28.485 ;
     RECT  2.16 28.755 49.68 29.025 ;
     RECT  2.16 29.295 49.68 29.565 ;
     RECT  2.16 29.835 49.68 30.105 ;
     RECT  2.16 30.375 49.68 30.645 ;
     RECT  2.16 30.915 49.68 31.185 ;
     RECT  2.16 31.455 49.68 31.725 ;
     RECT  2.16 31.995 49.68 32.265 ;
     RECT  2.16 32.535 49.68 32.805 ;
     RECT  2.16 33.075 49.68 33.345 ;
     RECT  2.16 33.615 49.68 33.885 ;
     RECT  2.16 34.155 49.68 34.425 ;
     RECT  2.16 34.695 49.68 34.965 ;
     RECT  2.16 35.235 49.68 35.505 ;
     RECT  2.16 35.775 49.68 36.045 ;
     RECT  2.16 36.315 49.68 36.585 ;
     RECT  2.16 36.855 49.68 37.125 ;
     RECT  2.16 37.395 49.68 37.665 ;
     RECT  2.16 37.935 49.68 38.205 ;
     RECT  2.16 38.475 49.68 38.745 ;
     RECT  2.16 39.015 49.68 39.285 ;
     RECT  2.16 39.555 49.68 39.825 ;
     RECT  2.16 40.095 49.68 40.365 ;
     RECT  2.16 40.635 49.68 40.905 ;
     RECT  2.16 41.175 49.68 41.445 ;
     RECT  2.16 41.715 49.68 41.985 ;
     RECT  2.16 42.255 49.68 42.525 ;
     RECT  2.16 42.795 49.68 43.065 ;
     RECT  2.16 43.335 49.68 43.605 ;
     RECT  2.16 43.875 49.68 44.145 ;
     RECT  2.16 44.415 49.68 44.685 ;
     RECT  2.16 44.955 49.68 45.225 ;
     RECT  2.16 45.495 49.68 45.765 ;
     RECT  2.16 46.035 49.68 46.305 ;
     RECT  2.16 46.575 49.68 46.845 ;
     RECT  2.16 47.115 49.68 47.385 ;
     RECT  2.16 47.655 49.68 47.925 ;
     RECT  2.16 48.195 49.68 48.465 ;
     RECT  2.16 48.735 49.68 49.005 ;
     RECT  2.16 49.275 49.68 49.545 ;
    LAYER M1 ;
     RECT  2.16 2.151 49.68 49.689 ;
    LAYER M2 ;
     RECT  0.103 27.342 2.155 27.36 ;
     RECT  1.723 28.152 2.155 28.17 ;
     RECT  0.103 11.448 2.16 11.466 ;
     RECT  0.103 16.11 2.16 16.128 ;
     RECT  2.155 27.342 2.16 28.17 ;
     RECT  2.155 28.962 2.16 29.394 ;
     RECT  1.831 30.924 2.16 30.942 ;
     RECT  0.103 33.39 2.16 33.408 ;
     RECT  2.155 35.01 2.16 35.028 ;
     RECT  2.16 2.151 49.68 49.689 ;
     RECT  49.68 27.036 50.675 27.864 ;
     RECT  49.68 24.138 50.711 24.894 ;
     RECT  49.68 25.686 50.711 26.244 ;
     RECT  50.675 27.036 50.711 27.63 ;
    LAYER M3 ;
     RECT  2.415 2.143 2.505 2.413 ;
     RECT  7.815 2.143 7.905 2.413 ;
     RECT  13.215 2.143 13.305 2.413 ;
     RECT  18.615 2.143 18.705 2.413 ;
     RECT  24.015 2.143 24.105 2.413 ;
     RECT  29.415 2.143 29.505 2.413 ;
     RECT  34.815 2.143 34.905 2.413 ;
     RECT  40.215 2.143 40.305 2.413 ;
     RECT  45.615 2.143 45.705 2.413 ;
     RECT  2.415 2.413 2.697 10.435 ;
     RECT  2.376 10.435 2.697 10.555 ;
     RECT  4.14 10.597 4.158 10.633 ;
     RECT  2.304 10.555 2.697 10.669 ;
     RECT  3.996 10.633 4.158 10.669 ;
     RECT  2.304 10.669 4.158 10.741 ;
     RECT  2.304 10.741 4.734 11.515 ;
     RECT  2.268 11.515 4.734 11.885 ;
     RECT  2.34 11.885 4.734 12.245 ;
     RECT  0.108 11.443 0.126 12.749 ;
     RECT  5.904 11.911 5.922 12.901 ;
     RECT  2.415 12.245 3.87 13.027 ;
     RECT  2.304 13.027 3.87 13.171 ;
     RECT  4.644 12.245 4.734 13.171 ;
     RECT  2.304 13.171 4.734 13.441 ;
     RECT  5.508 12.901 5.922 13.441 ;
     RECT  2.304 13.441 5.922 14.881 ;
     RECT  2.232 14.881 5.922 15.557 ;
     RECT  0.108 16.105 0.126 16.637 ;
     RECT  2.304 15.557 5.922 18.841 ;
     RECT  0.108 19.195 0.126 19.325 ;
     RECT  2.304 18.841 6.822 19.337 ;
     RECT  2.304 19.337 6.246 20.191 ;
     RECT  2.304 20.191 6.354 20.461 ;
     RECT  2.304 20.461 6.678 20.695 ;
     RECT  7.815 2.413 8.097 20.695 ;
     RECT  2.304 20.695 8.097 21.245 ;
     RECT  2.304 21.245 6.678 22.981 ;
     RECT  2.304 22.981 6.858 23.117 ;
     RECT  19.944 23.089 19.962 23.611 ;
     RECT  2.304 23.117 6.678 23.629 ;
     RECT  19.944 23.611 20.61 23.657 ;
     RECT  21.06 23.701 21.078 23.819 ;
     RECT  10.836 23.803 10.854 23.933 ;
     RECT  15.192 23.611 15.21 23.933 ;
     RECT  49.068 23.935 49.086 23.971 ;
     RECT  19.944 23.657 19.962 24.097 ;
     RECT  47.34 18.841 47.358 24.097 ;
     RECT  47.34 24.097 48.042 24.169 ;
     RECT  49.068 23.971 49.194 24.205 ;
     RECT  14.832 24.097 14.922 24.233 ;
     RECT  2.268 23.629 6.678 24.241 ;
     RECT  18.615 2.413 18.897 24.241 ;
     RECT  47.16 24.169 48.042 24.241 ;
     RECT  49.068 24.205 49.338 24.241 ;
     RECT  18.615 24.241 18.99 24.331 ;
     RECT  47.16 24.241 49.338 24.359 ;
     RECT  47.16 24.359 48.474 24.395 ;
     RECT  18.615 24.331 19.026 24.439 ;
     RECT  19.872 24.097 19.962 24.439 ;
     RECT  14.904 24.233 14.922 24.467 ;
     RECT  18.615 24.439 19.962 24.475 ;
     RECT  18.612 24.475 19.962 24.512 ;
     RECT  45.615 2.413 45.897 24.601 ;
     RECT  45.576 24.601 45.897 24.637 ;
     RECT  9.396 19.741 9.414 24.701 ;
     RECT  45.576 24.637 46.386 24.781 ;
     RECT  47.16 24.395 48.186 24.781 ;
     RECT  50.688 24.133 50.706 24.781 ;
     RECT  45.576 24.781 48.186 24.899 ;
     RECT  45.576 24.899 46.854 24.935 ;
     RECT  12.24 23.899 12.258 25.015 ;
     RECT  13.215 2.413 13.497 25.015 ;
     RECT  50.652 24.781 50.706 25.037 ;
     RECT  44.1 21.433 44.118 25.051 ;
     RECT  49.356 24.709 49.374 25.169 ;
     RECT  43.956 25.051 44.118 25.177 ;
     RECT  43.956 25.177 44.766 25.249 ;
     RECT  43.92 25.249 44.766 25.321 ;
     RECT  42.516 21.541 42.534 25.439 ;
     RECT  18.615 24.512 19.962 25.447 ;
     RECT  2.268 24.241 6.858 25.475 ;
     RECT  43.308 25.321 44.766 25.475 ;
     RECT  43.308 25.475 44.514 25.547 ;
     RECT  14.832 25.447 14.85 25.583 ;
     RECT  47.988 24.899 48.186 25.591 ;
     RECT  42.372 25.555 42.39 25.613 ;
     RECT  45.576 24.935 46.782 25.675 ;
     RECT  18.615 25.447 20.178 25.709 ;
     RECT  43.164 25.555 43.182 25.709 ;
     RECT  18.615 25.709 19.962 25.979 ;
     RECT  18.615 25.979 19.71 26.015 ;
     RECT  47.988 25.591 48.33 26.095 ;
     RECT  47.952 26.095 48.33 26.131 ;
     RECT  47.952 26.131 49.05 26.249 ;
     RECT  45.576 25.675 47.178 26.599 ;
     RECT  2.268 25.475 5.922 26.635 ;
     RECT  6.768 25.475 6.858 26.635 ;
     RECT  7.815 21.245 8.097 26.635 ;
     RECT  43.92 25.547 43.938 26.635 ;
     RECT  2.268 26.635 6.858 26.663 ;
     RECT  45.36 26.599 47.178 26.671 ;
     RECT  12.24 25.015 13.497 26.731 ;
     RECT  43.92 26.635 44.118 26.789 ;
     RECT  45.36 26.671 47.214 26.789 ;
     RECT  47.988 26.249 48.87 26.789 ;
     RECT  49.608 26.299 49.626 26.789 ;
     RECT  18.615 26.015 19.494 26.797 ;
     RECT  44.028 26.789 44.118 26.797 ;
     RECT  45.36 26.789 46.53 26.797 ;
     RECT  48.348 26.789 48.87 26.825 ;
     RECT  18.615 26.797 19.566 26.869 ;
     RECT  2.268 26.663 6.822 26.971 ;
     RECT  48.348 26.825 48.474 27.095 ;
     RECT  11.988 26.731 13.497 27.163 ;
     RECT  42.516 26.941 42.534 27.163 ;
     RECT  50.688 25.037 50.706 27.163 ;
     RECT  10.836 27.067 10.854 27.167 ;
     RECT  44.028 26.797 46.53 27.167 ;
     RECT  1.728 26.971 6.822 27.329 ;
     RECT  17.676 26.869 19.566 27.337 ;
     RECT  20.484 26.905 20.502 27.337 ;
     RECT  42.372 27.163 42.534 27.337 ;
     RECT  7.815 26.635 8.19 27.341 ;
     RECT  11.988 27.163 13.59 27.341 ;
     RECT  42.372 27.337 43.146 27.365 ;
     RECT  17.676 27.337 20.502 27.373 ;
     RECT  0.108 27.337 0.126 27.437 ;
     RECT  17.676 27.373 20.61 27.481 ;
     RECT  11.988 27.341 13.497 27.509 ;
     RECT  44.028 27.167 44.442 27.599 ;
     RECT  42.912 27.365 43.146 27.635 ;
     RECT  44.028 27.599 44.262 27.635 ;
     RECT  50.652 27.163 50.706 27.635 ;
     RECT  45.615 27.167 46.53 27.671 ;
     RECT  17.208 27.481 20.61 27.677 ;
     RECT  42.912 27.635 42.93 27.707 ;
     RECT  44.244 27.635 44.262 27.707 ;
     RECT  47.412 27.643 47.43 27.715 ;
     RECT  49.32 27.481 49.338 27.715 ;
     RECT  6.768 27.329 6.822 27.751 ;
     RECT  7.815 27.341 8.097 27.751 ;
     RECT  40.215 2.413 40.497 27.751 ;
     RECT  46.836 27.715 47.43 27.751 ;
     RECT  17.208 27.677 19.566 27.869 ;
     RECT  50.652 27.635 50.67 27.869 ;
     RECT  40.215 27.751 41.058 27.905 ;
     RECT  46.836 27.751 47.574 27.905 ;
     RECT  49.248 27.715 49.338 27.905 ;
     RECT  48.348 27.095 48.366 27.913 ;
     RECT  46.836 27.905 47.43 27.917 ;
     RECT  17.208 27.869 19.494 27.931 ;
     RECT  6.768 27.751 6.858 27.941 ;
     RECT  47.412 27.917 47.43 27.941 ;
     RECT  20.412 27.677 20.61 28.013 ;
     RECT  48.348 27.913 48.474 28.021 ;
     RECT  49.248 27.905 49.266 28.021 ;
     RECT  48.312 28.021 49.266 28.139 ;
     RECT  1.728 27.329 5.922 28.175 ;
     RECT  48.312 28.139 48.582 28.175 ;
     RECT  12.24 27.509 13.497 28.319 ;
     RECT  16.848 27.931 19.494 28.409 ;
     RECT  17.676 28.409 19.494 28.445 ;
     RECT  12.672 28.319 13.497 29.129 ;
     RECT  17.784 28.445 19.494 29.323 ;
     RECT  17.424 29.323 19.494 29.363 ;
     RECT  2.16 28.175 5.922 29.995 ;
     RECT  24.015 2.413 24.297 30.271 ;
     RECT  24.015 30.271 24.786 30.365 ;
     RECT  25.884 30.415 25.902 30.605 ;
     RECT  1.836 29.995 5.922 30.947 ;
     RECT  13.215 29.129 13.497 32.701 ;
     RECT  20.592 28.013 20.61 32.827 ;
     RECT  18 29.363 19.494 32.971 ;
     RECT  20.592 32.827 20.934 32.971 ;
     RECT  18 32.971 20.934 32.999 ;
     RECT  12.888 32.701 13.497 33.007 ;
     RECT  16.884 32.827 16.902 33.241 ;
     RECT  12.78 33.007 13.497 33.293 ;
     RECT  16.884 33.241 17.01 33.293 ;
     RECT  16.884 33.293 16.902 33.305 ;
     RECT  18 32.999 20.61 33.809 ;
     RECT  0.108 33.385 0.126 33.917 ;
     RECT  2.16 30.947 5.922 35.033 ;
     RECT  2.268 35.033 5.922 35.735 ;
     RECT  18 33.809 19.818 37.319 ;
     RECT  19.8 37.319 19.818 37.435 ;
     RECT  2.304 35.735 5.922 37.859 ;
     RECT  0.108 37.771 0.126 37.901 ;
     RECT  7.704 27.751 8.097 38.155 ;
     RECT  18 37.319 18.897 38.203 ;
     RECT  19.8 37.435 19.854 38.203 ;
     RECT  20.592 33.809 20.61 38.203 ;
     RECT  5.148 37.859 5.922 38.479 ;
     RECT  6.768 27.941 6.786 38.479 ;
     RECT  17.424 38.203 18.897 38.515 ;
     RECT  2.304 37.859 4.23 38.669 ;
     RECT  2.304 38.669 3.438 38.705 ;
     RECT  4.176 38.669 4.23 38.713 ;
     RECT  5.148 38.479 6.786 38.713 ;
     RECT  7.524 38.155 8.097 38.713 ;
     RECT  4.176 38.713 6.786 38.765 ;
     RECT  17.316 38.515 18.897 38.765 ;
     RECT  19.8 38.203 20.61 38.765 ;
     RECT  5.004 38.765 6.786 38.939 ;
     RECT  2.34 38.705 3.438 38.975 ;
     RECT  4.176 38.765 4.194 38.975 ;
     RECT  5.04 38.939 6.786 39.019 ;
     RECT  7.524 38.713 8.694 39.019 ;
     RECT  2.412 38.975 3.438 39.209 ;
     RECT  2.412 39.209 3.15 39.245 ;
     RECT  5.04 39.019 8.694 39.595 ;
     RECT  5.04 39.595 8.766 39.721 ;
     RECT  4.572 39.721 8.766 39.749 ;
     RECT  4.572 39.749 8.694 39.901 ;
     RECT  4.212 39.901 8.694 39.929 ;
     RECT  2.412 39.245 2.697 39.931 ;
     RECT  4.212 39.929 6.534 40.019 ;
     RECT  2.304 39.931 2.697 40.055 ;
     RECT  2.412 40.055 2.697 40.135 ;
     RECT  4.212 40.019 6.462 40.135 ;
     RECT  2.412 40.135 3.294 40.171 ;
     RECT  4.104 40.135 6.462 40.171 ;
     RECT  7.524 39.929 8.694 40.199 ;
     RECT  2.412 40.171 6.462 40.559 ;
     RECT  2.412 40.559 3.15 40.595 ;
     RECT  3.996 40.559 4.302 40.595 ;
     RECT  2.412 40.595 2.697 40.795 ;
     RECT  5.148 40.559 6.462 40.829 ;
     RECT  19.8 38.765 19.854 40.829 ;
     RECT  5.148 40.829 6.138 40.865 ;
     RECT  19.836 40.829 19.854 40.945 ;
     RECT  20.592 38.765 20.61 40.945 ;
     RECT  5.328 40.865 6.138 40.973 ;
     RECT  5.328 40.973 5.922 41.099 ;
     RECT  3.996 40.595 4.014 41.135 ;
     RECT  2.304 40.795 2.697 41.405 ;
     RECT  2.415 41.405 2.697 41.521 ;
     RECT  2.415 41.521 2.862 41.639 ;
     RECT  7.815 40.199 8.694 41.639 ;
     RECT  7.815 41.639 8.298 41.755 ;
     RECT  7.488 41.755 8.298 41.792 ;
     RECT  7.632 41.792 8.298 41.909 ;
     RECT  3.888 41.791 3.906 41.945 ;
     RECT  7.815 41.909 8.298 41.981 ;
     RECT  5.58 41.099 5.922 42.719 ;
     RECT  13.215 33.293 13.497 42.727 ;
     RECT  12.564 42.727 13.497 43.528 ;
     RECT  12.564 43.528 13.806 43.681 ;
     RECT  12.564 43.681 14.166 43.901 ;
     RECT  17.136 45.535 17.154 45.571 ;
     RECT  18 38.765 18.897 45.571 ;
     RECT  17.136 45.571 18.897 45.581 ;
     RECT  17.46 45.581 18.897 45.661 ;
     RECT  19.836 40.945 20.61 45.661 ;
     RECT  12.564 43.901 13.497 45.725 ;
     RECT  14.832 45.697 14.85 45.869 ;
     RECT  5.58 42.719 5.598 45.959 ;
     RECT  29.415 2.413 29.697 46.003 ;
     RECT  29.415 46.003 30.186 46.111 ;
     RECT  17.46 45.661 20.61 46.229 ;
     RECT  29.415 46.111 30.474 46.229 ;
     RECT  17.46 46.229 20.574 46.315 ;
     RECT  5.472 46.111 5.49 46.409 ;
     RECT  16.56 46.741 16.578 46.777 ;
     RECT  16.02 46.777 16.578 46.813 ;
     RECT  15.984 46.813 16.578 46.885 ;
     RECT  17.316 46.315 20.574 46.885 ;
     RECT  15.192 46.747 15.21 46.921 ;
     RECT  15.984 46.885 20.574 46.921 ;
     RECT  24.015 30.365 24.297 47.035 ;
     RECT  25.056 47.011 25.074 47.035 ;
     RECT  15.192 46.921 20.574 47.083 ;
     RECT  7.815 41.981 8.154 47.111 ;
     RECT  15.192 47.083 20.754 47.183 ;
     RECT  17.172 47.183 20.754 47.317 ;
     RECT  24.015 47.035 25.074 47.317 ;
     RECT  27.072 47.035 27.09 47.317 ;
     RECT  15.192 47.183 16.002 47.323 ;
     RECT  17.172 47.317 20.826 47.353 ;
     RECT  36.972 47.191 36.99 47.353 ;
     RECT  27.072 47.317 27.162 47.389 ;
     RECT  23.544 47.317 25.074 47.425 ;
     RECT  36.864 47.353 36.99 47.425 ;
     RECT  22.716 47.389 22.734 47.461 ;
     RECT  23.472 47.425 25.074 47.461 ;
     RECT  27.072 47.389 27.414 47.461 ;
     RECT  28.476 47.083 28.494 47.461 ;
     RECT  29.415 46.229 30.15 47.461 ;
     RECT  30.888 47.353 30.906 47.461 ;
     RECT  14.544 47.323 16.002 47.579 ;
     RECT  17.172 47.353 20.898 47.587 ;
     RECT  27.072 47.461 27.522 47.623 ;
     RECT  28.404 47.461 28.494 47.623 ;
     RECT  14.544 47.579 14.562 47.651 ;
     RECT  22.716 47.461 25.074 47.695 ;
     RECT  36.792 47.425 36.99 47.695 ;
     RECT  17.172 47.587 20.97 47.731 ;
     RECT  22.716 47.695 25.758 47.731 ;
     RECT  27.072 47.623 28.494 47.731 ;
     RECT  29.415 47.461 30.906 47.731 ;
     RECT  17.172 47.731 21.042 47.821 ;
     RECT  32.724 47.317 32.742 47.821 ;
     RECT  34.815 2.413 35.097 47.821 ;
     RECT  36.576 47.695 36.99 47.821 ;
     RECT  15.336 47.579 16.002 47.849 ;
     RECT  22.212 47.731 30.906 47.851 ;
     RECT  31.752 47.821 31.77 47.851 ;
     RECT  32.544 47.821 32.742 47.851 ;
     RECT  34.452 47.821 35.097 47.851 ;
     RECT  36.072 47.821 36.99 47.851 ;
     RECT  22.212 47.851 32.742 47.891 ;
     RECT  31.752 47.891 32.742 47.965 ;
     RECT  34.164 47.851 36.99 48.001 ;
     RECT  17.172 47.821 21.438 48.091 ;
     RECT  22.212 47.891 30.834 48.119 ;
     RECT  31.752 47.965 32.958 48.119 ;
     RECT  33.912 48.001 37.17 48.119 ;
     RECT  22.212 48.119 30.798 48.191 ;
     RECT  33.912 48.119 36.954 48.229 ;
     RECT  22.212 48.191 30.726 48.263 ;
     RECT  33.66 48.229 36.954 48.269 ;
     RECT  15.696 47.849 16.002 48.271 ;
     RECT  17.1 48.091 21.438 48.271 ;
     RECT  22.212 48.263 28.422 48.299 ;
     RECT  29.415 48.263 30.726 48.389 ;
     RECT  15.696 48.271 21.438 48.475 ;
     RECT  22.212 48.299 28.35 48.475 ;
     RECT  15.696 48.475 28.35 48.659 ;
     RECT  29.415 48.389 30.474 48.659 ;
     RECT  31.752 48.119 32.814 48.659 ;
     RECT  33.948 48.269 36.954 48.659 ;
     RECT  31.752 48.659 32.526 48.929 ;
     RECT  31.752 48.929 32.454 49.045 ;
     RECT  33.948 48.659 35.097 49.045 ;
     RECT  29.415 48.659 30.33 49.199 ;
     RECT  31.608 49.045 32.454 49.199 ;
     RECT  35.928 48.659 36.81 49.199 ;
     RECT  2.415 41.639 2.697 49.427 ;
     RECT  7.815 47.111 8.097 49.427 ;
     RECT  13.215 45.725 13.497 49.427 ;
     RECT  40.215 27.905 40.497 49.427 ;
     RECT  45.615 27.671 45.897 49.427 ;
     RECT  15.696 48.659 28.242 49.469 ;
     RECT  29.415 49.199 30.258 49.469 ;
     RECT  31.608 49.199 32.418 49.469 ;
     RECT  35.928 49.199 36.738 49.469 ;
     RECT  15.696 49.469 27.702 49.517 ;
     RECT  29.415 49.469 30.078 49.517 ;
     RECT  31.608 49.469 32.238 49.517 ;
     RECT  33.84 49.045 35.097 49.517 ;
     RECT  35.928 49.469 36.558 49.517 ;
     RECT  34.815 49.517 35.097 49.531 ;
     RECT  29.415 49.517 29.754 49.549 ;
     RECT  15.696 49.517 15.966 49.565 ;
     RECT  16.92 49.517 27.702 49.565 ;
     RECT  16.92 49.565 27.27 49.577 ;
     RECT  28.908 49.549 29.754 49.577 ;
     RECT  31.068 49.531 31.086 49.577 ;
     RECT  33.228 49.531 33.246 49.577 ;
     RECT  34.815 49.531 35.406 49.577 ;
     RECT  2.415 49.427 2.505 49.697 ;
     RECT  7.815 49.427 7.905 49.697 ;
     RECT  13.215 49.427 13.305 49.697 ;
     RECT  23.832 49.577 24.105 49.697 ;
     RECT  34.815 49.577 34.905 49.697 ;
     RECT  40.215 49.427 40.305 49.697 ;
     RECT  45.615 49.427 45.705 49.697 ;
     RECT  18.216 49.577 18.774 49.805 ;
     RECT  28.908 49.577 29.646 49.805 ;
     RECT  26.748 49.577 27.27 50.717 ;
     RECT  15.948 49.565 15.966 50.765 ;
     RECT  18.216 49.805 18.234 50.765 ;
     RECT  22.104 49.577 22.122 50.765 ;
     RECT  23.832 49.697 23.85 50.765 ;
     RECT  26.748 50.717 26.766 50.765 ;
     RECT  28.908 49.805 28.926 50.765 ;
    LAYER M4 ;
     RECT  0.06 10.56 0.179 41.256 ;
     RECT  0.179 10.56 2.293 16.2 ;
     RECT  2.293 10.56 2.408 16.296 ;
     RECT  0.179 17.472 2.408 41.256 ;
     RECT  2.408 2.148 2.512 49.692 ;
     RECT  2.512 2.418 2.704 49.422 ;
     RECT  2.704 16.272 2.765 25.512 ;
     RECT  2.765 16.512 2.837 25.512 ;
     RECT  2.704 26.64 2.981 33.624 ;
     RECT  2.981 26.64 3.011 33.288 ;
     RECT  3.011 33.264 3.089 33.288 ;
     RECT  2.704 34.656 3.125 36.792 ;
     RECT  3.125 34.8 3.197 36.792 ;
     RECT  2.704 12.48 3.34 15.288 ;
     RECT  2.837 16.512 3.443 24.408 ;
     RECT  3.34 13.104 3.521 15.288 ;
     RECT  3.011 26.64 3.521 32.184 ;
     RECT  3.197 34.8 3.521 35.064 ;
     RECT  3.521 13.104 3.593 13.656 ;
     RECT  3.521 14.736 3.593 15.288 ;
     RECT  3.443 16.944 3.665 24.408 ;
     RECT  3.593 13.584 3.724 13.656 ;
     RECT  3.665 18.192 3.773 24.408 ;
     RECT  3.773 18.576 3.845 24.408 ;
     RECT  2.704 10.704 3.925 11.496 ;
     RECT  3.724 13.584 3.953 13.608 ;
     RECT  3.925 10.656 3.971 11.496 ;
     RECT  3.971 10.656 4.025 10.68 ;
     RECT  3.521 30.816 4.025 32.184 ;
     RECT  3.593 14.736 4.061 14.76 ;
     RECT  4.025 31.536 4.061 32.184 ;
     RECT  3.845 18.768 4.129 24.408 ;
     RECT  2.837 25.488 4.129 25.512 ;
     RECT  4.129 18.768 4.165 25.512 ;
     RECT  3.521 26.64 4.165 29.784 ;
     RECT  3.197 36.72 4.201 36.792 ;
     RECT  2.704 38.16 4.201 38.184 ;
     RECT  4.061 31.536 4.241 31.56 ;
     RECT  3.521 34.896 4.241 35.064 ;
     RECT  4.201 36.72 4.345 38.184 ;
     RECT  4.165 18.768 4.393 29.784 ;
     RECT  3.665 16.944 4.403 16.968 ;
     RECT  4.393 29.136 4.451 29.784 ;
     RECT  4.241 35.04 4.493 35.064 ;
     RECT  4.345 36.672 4.595 38.184 ;
     RECT  4.451 29.664 4.601 29.784 ;
     RECT  4.393 18.768 4.637 27.48 ;
     RECT  4.637 18.864 4.673 27.48 ;
     RECT  4.673 19.008 4.709 27.48 ;
     RECT  4.595 36.672 4.745 36.696 ;
     RECT  4.595 38.16 4.813 38.184 ;
     RECT  2.704 40.272 4.817 40.296 ;
     RECT  4.709 19.008 4.853 27.384 ;
     RECT  4.853 20.16 4.861 27.384 ;
     RECT  4.861 20.16 4.883 27.336 ;
     RECT  4.853 19.008 4.889 19.176 ;
     RECT  4.883 25.104 4.961 27.336 ;
     RECT  4.883 20.16 5.069 23.832 ;
     RECT  4.961 25.104 5.069 27.144 ;
     RECT  5.069 25.824 5.075 27.144 ;
     RECT  5.029 35.904 5.113 35.928 ;
     RECT  5.069 20.784 5.123 23.832 ;
     RECT  4.889 19.008 5.177 19.032 ;
     RECT  5.075 26.64 5.177 27.144 ;
     RECT  5.177 26.64 5.285 27.048 ;
     RECT  4.813 38.16 5.365 38.76 ;
     RECT  5.101 39.888 5.365 39.912 ;
     RECT  5.123 20.784 5.429 22.104 ;
     RECT  5.365 38.16 5.789 39.912 ;
     RECT  5.429 22.08 6.005 22.104 ;
     RECT  5.789 38.16 6.437 39.336 ;
     RECT  5.429 20.784 7.244 20.856 ;
     RECT  5.285 26.64 7.285 26.664 ;
     RECT  6.437 38.16 7.429 38.184 ;
     RECT  6.437 39.312 7.429 39.336 ;
     RECT  7.244 20.784 7.808 21.24 ;
     RECT  5.123 23.808 7.808 23.832 ;
     RECT  7.285 26.64 7.808 27.192 ;
     RECT  4.601 29.76 7.808 29.784 ;
     RECT  7.429 38.16 7.808 39.336 ;
     RECT  7.477 41.76 7.808 41.784 ;
     RECT  7.808 2.148 7.912 49.692 ;
     RECT  7.912 2.418 8.104 49.422 ;
     RECT  8.104 26.64 8.201 27.336 ;
     RECT  8.104 23.808 10.825 23.832 ;
     RECT  10.825 23.808 10.865 23.928 ;
     RECT  8.201 26.736 12.017 27.336 ;
     RECT  12.017 27.168 12.197 27.336 ;
     RECT  10.865 23.904 13.208 23.928 ;
     RECT  12.197 27.168 13.208 27.192 ;
     RECT  12.769 33.264 13.208 33.288 ;
     RECT  8.104 41.76 13.208 41.784 ;
     RECT  13.208 2.148 13.312 49.692 ;
     RECT  13.312 2.418 13.504 49.422 ;
     RECT  13.504 27.168 13.601 27.336 ;
     RECT  13.504 41.76 13.955 41.784 ;
     RECT  13.504 43.536 14.531 43.896 ;
     RECT  14.485 46.752 14.533 46.776 ;
     RECT  14.533 46.752 14.819 47.352 ;
     RECT  13.504 23.904 15.181 23.928 ;
     RECT  15.181 23.616 15.221 23.928 ;
     RECT  14.819 46.752 15.221 46.776 ;
     RECT  15.685 49.536 15.779 49.56 ;
     RECT  15.937 50.736 16.211 50.76 ;
     RECT  16.597 49.488 16.697 49.512 ;
     RECT  13.601 27.312 16.837 27.336 ;
     RECT  13.504 33.024 16.873 33.288 ;
     RECT  16.837 27.312 16.981 27.96 ;
     RECT  16.873 32.832 17.021 33.288 ;
     RECT  16.981 27.312 17.065 28.2 ;
     RECT  17.125 47.04 17.132 47.064 ;
     RECT  16.729 48.288 17.132 48.312 ;
     RECT  17.132 47.04 17.173 48.312 ;
     RECT  16.981 38.208 17.305 38.232 ;
     RECT  17.084 45.552 17.305 45.576 ;
     RECT  17.173 47.04 17.305 48.504 ;
     RECT  14.531 43.536 17.363 43.56 ;
     RECT  17.305 45.552 17.363 48.504 ;
     RECT  17.065 27.312 17.411 27.96 ;
     RECT  17.365 29.328 17.453 29.352 ;
     RECT  17.305 38.208 17.459 38.76 ;
     RECT  15.301 30.336 17.557 30.36 ;
     RECT  17.317 34.752 17.603 34.776 ;
     RECT  17.411 27.312 17.917 27.624 ;
     RECT  18.205 50.736 18.371 50.76 ;
     RECT  15.221 23.616 18.601 23.64 ;
     RECT  18.601 23.616 18.608 24.504 ;
     RECT  17.917 26.88 18.608 27.624 ;
     RECT  17.557 30.336 18.608 30.6 ;
     RECT  17.021 32.832 18.608 33.048 ;
     RECT  18.181 37.632 18.608 38.04 ;
     RECT  17.363 46.32 18.608 48.504 ;
     RECT  16.909 49.536 18.608 49.56 ;
     RECT  18.608 2.148 18.712 49.692 ;
     RECT  18.712 2.418 18.716 49.692 ;
     RECT  18.716 2.418 18.803 49.8 ;
     RECT  18.803 2.418 18.904 49.56 ;
     RECT  18.904 30.336 19.001 30.6 ;
     RECT  18.904 23.616 19.081 25.704 ;
     RECT  19.081 23.616 19.225 25.08 ;
     RECT  18.904 26.88 19.253 27.336 ;
     RECT  18.904 46.32 19.331 48.504 ;
     RECT  19.331 47.04 19.372 48.504 ;
     RECT  18.904 36.48 19.379 37.032 ;
     RECT  19.372 48.48 19.379 48.504 ;
     RECT  19.379 36.48 19.397 36.504 ;
     RECT  18.904 32.832 19.649 33.048 ;
     RECT  19.253 27.312 20.012 27.336 ;
     RECT  20.012 27.312 20.099 27.672 ;
     RECT  20.053 38.208 20.113 38.232 ;
     RECT  20.113 38.208 20.197 38.76 ;
     RECT  20.197 38.208 20.261 38.232 ;
     RECT  19.372 47.04 20.509 47.496 ;
     RECT  19.225 23.616 20.621 24.504 ;
     RECT  19.649 32.832 20.945 32.856 ;
     RECT  20.621 23.712 21.107 24.504 ;
     RECT  20.509 47.04 21.269 47.88 ;
     RECT  22.093 50.736 22.259 50.76 ;
     RECT  21.517 48.48 22.277 48.504 ;
     RECT  21.269 47.04 23.425 47.064 ;
     RECT  23.821 50.736 23.987 50.76 ;
     RECT  21.061 25.584 24.008 25.608 ;
     RECT  20.099 27.312 24.008 27.336 ;
     RECT  19.001 30.336 24.008 30.504 ;
     RECT  23.425 47.04 24.008 47.928 ;
     RECT  18.904 49.536 24.008 49.56 ;
     RECT  24.008 2.148 24.112 49.692 ;
     RECT  24.112 2.418 24.304 49.56 ;
     RECT  24.304 30.336 24.797 30.6 ;
     RECT  24.304 47.04 25.369 47.064 ;
     RECT  25.369 47.04 25.841 47.928 ;
     RECT  24.797 30.576 25.913 30.6 ;
     RECT  24.304 49.536 26.579 49.56 ;
     RECT  26.737 50.736 27.011 50.76 ;
     RECT  27.241 50.688 27.443 50.712 ;
     RECT  25.841 47.04 27.529 47.064 ;
     RECT  27.673 49.536 27.875 49.56 ;
     RECT  27.529 47.04 28.465 47.832 ;
     RECT  28.897 50.736 29.171 50.76 ;
     RECT  24.304 25.584 29.408 25.608 ;
     RECT  24.304 27.312 29.408 27.336 ;
     RECT  28.465 47.04 29.408 47.928 ;
     RECT  29.408 2.148 29.512 49.692 ;
     RECT  29.512 2.418 29.557 49.692 ;
     RECT  29.557 2.418 29.657 49.8 ;
     RECT  29.657 2.418 29.704 49.512 ;
     RECT  29.704 46.08 29.801 47.928 ;
     RECT  29.704 49.488 30.089 49.512 ;
     RECT  29.801 46.08 30.131 47.88 ;
     RECT  31.057 49.536 31.331 49.56 ;
     RECT  30.131 47.856 31.921 47.88 ;
     RECT  31.921 47.856 31.961 48.264 ;
     RECT  31.717 49.488 32.249 49.512 ;
     RECT  33.217 49.536 33.491 49.56 ;
     RECT  31.961 48.24 34.153 48.264 ;
     RECT  29.704 25.584 34.808 25.608 ;
     RECT  29.704 27.312 34.808 27.336 ;
     RECT  34.153 47.856 34.808 48.264 ;
     RECT  33.877 49.488 34.808 49.512 ;
     RECT  34.808 2.148 34.912 49.692 ;
     RECT  34.912 2.418 35.104 49.56 ;
     RECT  35.104 49.488 35.651 49.56 ;
     RECT  35.651 49.488 36.569 49.512 ;
     RECT  35.104 47.856 36.605 47.88 ;
     RECT  35.104 25.584 40.208 25.608 ;
     RECT  35.104 27.312 40.208 27.336 ;
     RECT  40.208 2.148 40.312 49.692 ;
     RECT  40.312 2.418 40.504 49.422 ;
     RECT  40.504 27.168 42.332 27.192 ;
     RECT  42.332 27.168 42.373 27.336 ;
     RECT  42.373 27.168 42.401 27.912 ;
     RECT  42.401 27.312 42.419 27.912 ;
     RECT  40.504 25.584 43.945 25.608 ;
     RECT  43.945 25.056 43.949 25.608 ;
     RECT  43.949 25.056 45.565 25.08 ;
     RECT  45.565 24.624 45.608 25.08 ;
     RECT  42.419 27.888 45.608 27.912 ;
     RECT  45.608 2.148 45.712 49.692 ;
     RECT  45.712 2.418 45.904 49.422 ;
     RECT  45.904 27.888 46.865 27.912 ;
     RECT  45.904 24.624 47.125 24.648 ;
     RECT  47.125 24.192 47.171 24.648 ;
     RECT  47.105 25.68 47.189 25.704 ;
     RECT  47.171 24.192 47.212 24.216 ;
     RECT  49.597 26.304 50.641 26.328 ;
     RECT  50.641 25.008 50.677 25.032 ;
     RECT  50.641 26.304 50.677 27.192 ;
     RECT  50.677 24.144 51.804 27.624 ;
    LAYER M5 ;
     RECT  2.4 2.137 2.52 2.151 ;
     RECT  7.8 2.137 7.92 2.151 ;
     RECT  13.2 2.137 13.32 2.151 ;
     RECT  18.6 2.137 18.72 2.151 ;
     RECT  24 2.137 24.12 2.151 ;
     RECT  29.4 2.137 29.52 2.151 ;
     RECT  34.8 2.137 34.92 2.151 ;
     RECT  40.2 2.137 40.32 2.151 ;
     RECT  45.6 2.137 45.72 2.151 ;
     RECT  2.4 2.151 2.712 10.693 ;
     RECT  3.936 10.645 3.96 10.693 ;
     RECT  2.4 10.693 3.96 11.507 ;
     RECT  2.4 11.507 3.336 13.573 ;
     RECT  2.4 13.573 3.576 13.621 ;
     RECT  0.144 13.045 0.168 14.291 ;
     RECT  2.4 13.621 3.672 16.933 ;
     RECT  0.144 17.029 0.168 17.699 ;
     RECT  2.4 16.933 4.392 20.149 ;
     RECT  7.8 2.151 8.112 21.205 ;
     RECT  2.4 20.149 5.016 21.973 ;
     RECT  2.4 21.973 5.112 23.843 ;
     RECT  18.6 2.151 18.912 24.469 ;
     RECT  18.6 24.469 19.032 25.045 ;
     RECT  21.072 23.701 21.096 25.619 ;
     RECT  47.136 24.181 47.16 25.715 ;
     RECT  2.4 23.843 4.872 25.813 ;
     RECT  7.296 21.205 8.112 27.203 ;
     RECT  18.6 25.045 19.176 27.301 ;
     RECT  17.088 23.605 17.112 27.589 ;
     RECT  18.192 27.301 19.176 27.589 ;
     RECT  17.088 27.589 19.176 27.637 ;
     RECT  42.384 27.301 42.408 27.923 ;
     RECT  17.088 27.637 20.088 28.165 ;
     RECT  7.44 27.203 8.112 29.795 ;
     RECT  2.4 25.813 5.064 30.947 ;
     RECT  2.4 30.947 3.528 31.765 ;
     RECT  2.304 31.765 3.528 32.195 ;
     RECT  2.304 32.195 3.384 32.531 ;
     RECT  13.2 2.151 13.512 33.013 ;
     RECT  4.56 30.947 5.064 35.939 ;
     RECT  2.4 32.531 3.384 36.755 ;
     RECT  4.56 35.939 4.584 37.667 ;
     RECT  16.992 28.165 20.088 37.667 ;
     RECT  16.992 37.667 17.352 38.243 ;
     RECT  7.536 29.795 8.112 38.677 ;
     RECT  17.328 38.243 17.352 38.725 ;
     RECT  18.336 37.667 20.088 38.725 ;
     RECT  7.44 38.677 8.112 39.347 ;
     RECT  5.376 38.725 5.4 39.923 ;
     RECT  13.2 33.013 13.944 43.861 ;
     RECT  15.312 30.325 15.336 43.861 ;
     RECT  13.2 43.861 15.336 43.907 ;
     RECT  17.328 38.725 20.184 45.541 ;
     RECT  29.4 2.151 29.712 46.069 ;
     RECT  14.496 43.907 15.336 46.787 ;
     RECT  17.136 45.541 20.184 47.075 ;
     RECT  29.4 46.069 30.12 47.075 ;
     RECT  14.784 46.787 15.336 47.363 ;
     RECT  17.184 47.075 20.184 47.363 ;
     RECT  17.184 47.363 19.368 47.747 ;
     RECT  18.336 47.747 19.368 47.939 ;
     RECT  17.184 47.747 17.208 48.515 ;
     RECT  18.6 47.939 19.368 48.515 ;
     RECT  29.4 47.075 29.712 49.477 ;
     RECT  34.8 2.151 35.112 49.477 ;
     RECT  15.312 47.363 15.336 49.525 ;
     RECT  16.608 49.477 16.632 49.525 ;
     RECT  18.6 48.515 18.912 49.525 ;
     RECT  24 2.151 24.312 49.525 ;
     RECT  31.728 49.477 32.184 49.525 ;
     RECT  33.888 49.477 36.504 49.525 ;
     RECT  2.4 36.755 2.712 49.689 ;
     RECT  7.8 39.347 8.112 49.689 ;
     RECT  13.2 43.907 13.512 49.689 ;
     RECT  40.2 2.151 40.512 49.689 ;
     RECT  45.6 2.151 45.912 49.689 ;
     RECT  2.4 49.689 2.52 49.703 ;
     RECT  7.8 49.689 7.92 49.703 ;
     RECT  13.2 49.689 13.32 49.703 ;
     RECT  29.4 49.477 30.024 49.703 ;
     RECT  33.456 49.525 36.504 49.703 ;
     RECT  40.2 49.689 40.32 49.703 ;
     RECT  45.6 49.689 45.72 49.703 ;
     RECT  15.312 49.525 26.568 50.677 ;
     RECT  27.84 49.525 27.864 50.677 ;
     RECT  29.568 49.703 30.024 50.725 ;
     RECT  15.312 50.677 27.864 51.792 ;
     RECT  29.136 50.725 30.024 51.792 ;
     RECT  31.296 49.525 32.184 51.792 ;
     RECT  33.456 49.703 34.344 51.792 ;
     RECT  35.616 49.703 36.504 51.792 ;
     RECT  2.712 10.645 3.936 10.693 ;
     RECT  17.112 23.605 18.6 27.301 ;
     RECT  45.912 24.181 47.136 25.715 ;
     RECT  17.112 27.301 18.192 27.589 ;
     RECT  3.528 30.947 4.56 32.195 ;
     RECT  3.384 32.195 4.56 36.755 ;
     RECT  13.944 33.013 15.312 43.861 ;
     RECT  17.352 37.667 18.336 38.725 ;
     RECT  13.512 43.907 14.496 46.787 ;
     RECT  13.512 46.787 14.784 47.363 ;
     RECT  17.208 47.747 18.336 47.939 ;
     RECT  17.208 47.939 18.6 48.515 ;
     RECT  17.184 48.515 18.6 49.477 ;
     RECT  18.912 48.515 19.368 49.525 ;
     RECT  15.336 49.477 16.608 49.525 ;
     RECT  16.632 49.477 18.6 49.525 ;
     RECT  26.568 49.525 27.84 50.677 ;
     RECT  30.024 49.525 31.296 51.708 ;
     RECT  32.184 49.525 33.456 51.708 ;
     RECT  29.4 49.703 29.568 50.725 ;
     RECT  34.344 49.703 35.616 51.708 ;
     RECT  27.864 50.725 29.136 51.708 ;
     RECT  27.912 51.708 28.224 51.792 ;
     RECT  28.344 51.708 28.656 51.792 ;
     RECT  28.776 51.708 29.088 51.792 ;
     RECT  30.072 51.708 30.384 51.792 ;
     RECT  30.504 51.708 30.816 51.792 ;
     RECT  30.936 51.708 31.248 51.792 ;
     RECT  32.232 51.708 32.544 51.792 ;
     RECT  32.664 51.708 32.976 51.792 ;
     RECT  33.096 51.708 33.408 51.792 ;
     RECT  34.392 51.708 34.704 51.792 ;
     RECT  34.824 51.708 35.136 51.792 ;
     RECT  35.256 51.708 35.568 51.792 ;
  END
END dsfd_vm_static_read_v2_p
END LIBRARY
